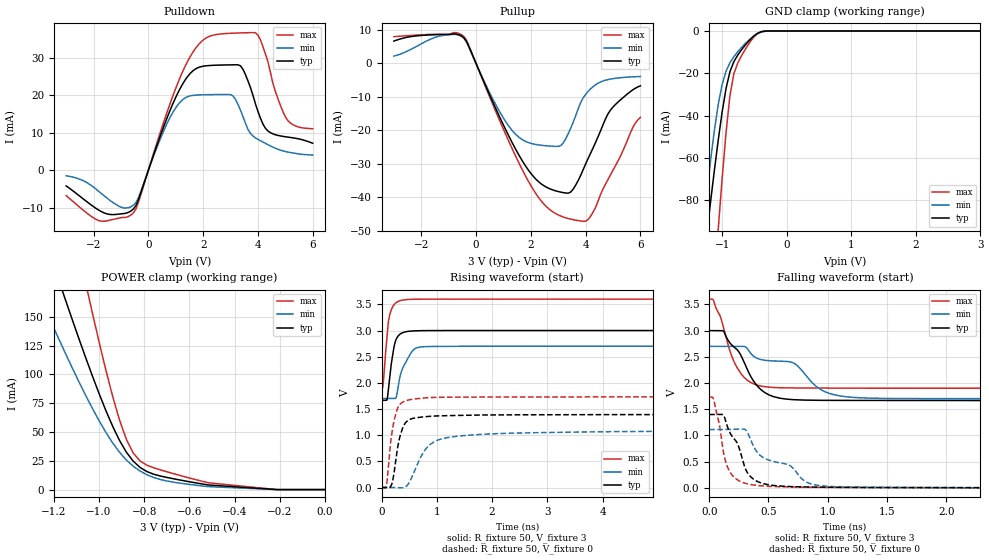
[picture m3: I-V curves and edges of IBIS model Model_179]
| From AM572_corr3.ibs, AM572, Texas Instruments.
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| Model based on original model for SDIO1833PB_H
|   Sub model 66OHMS_3
[model]   Model_179
|[Description]  [3V-I/O-X-X]
|   , ,
|[Input Load]
|[Output Drive]
|Voltage   3V
|Mode   I/O
Model_type   I/O
Polarity   Non-Inverting
Enable   Active-Low
Vinl =   0.75
Vinh =   1.875
Cref =   15.0000pF
Rref =   100.0000M
Vref =   0V
Vmeas =   1.5
C_comp   5p   5p   5p
[Model Spec]
Vinl   0.75   0.675   0.9
Vinh   1.875   1.6875   2.25
[Temperature Range]   25   125   -40
[Voltage Range]   3   2.7   3.6
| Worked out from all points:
|   slope of the pulldown table from 0 to 0.45 V, typ, clamps not added: 47.7 ohm
|   slope of the pullup table from 0 to 0.45 V, typ, clamps not added: 52.5 ohm
|   GND clamp passes 1 mA (typ) near -0.44 V on its own axis
|   rising waveform, R_fixture 50, V_fixture 3: 20-80 % time 105ps typ, 196ps min, 91ps max; typ from 1.67 V to 3 V
|   rising waveform, R_fixture 50, V_fixture 0: 20-80 % time 150ps typ, 422ps min, 132ps max; typ from 0 V to 1.4 V
|   falling waveform, R_fixture 50, V_fixture 3: 20-80 % time 223ps typ, 544ps min, 154ps max; typ from 3 V to 1.67 V
|   falling waveform, R_fixture 50, V_fixture 0: 20-80 % time 164ps typ, 406ps min, 97.3ps max; typ from 1.4 V to 0 V
[POWER_clamp]
-3V       1.325A     1.066A     2.083A
-1.273V   237.5mA    172.4mA    376.8mA
-1.242V   219.5mA    158.9mA    348.1mA
-1.152V   166.4mA    119.5mA    263mA
-1.061V   115.4mA    82.4mA     180.6mA
-1.03V    99.16mA    70.84mA    154.1mA
-969.7mV  68.62mA    49.67mA    103.8mA
-909.1mV  42.6mA     32.36mA    60.24mA
-878.8mV  32.4mA     25.65mA    43.46mA
-818.2mV  19.2mA     16.11mA    24.78mA
-515.2mV  4.001mA    2.562mA    5.883mA
0V        300.2nA    570.7nA    4.935uA
[Pulldown]
-3V       -4.151mA   -1.456mA   -6.73mA
-1.727V   -10.94mA   -6.093mA   -13.52mA
-545.5mV  -10.3mA    -9.288mA   -11.31mA
1V        19.41mA    16.64mA    21.82mA
1.636V    26.52mA    19.93mA    31.53mA
2.364V    27.93mA    20.14mA    35.94mA
3.091V    28.06mA    19.77mA    36.48mA
3.364V    27.79mA    15.98mA    36.55mA
4V        15.67mA    8.228mA    36mA
4.364V    10.47mA    6.836mA    28.93mA
5V        8.926mA    4.995mA    14.24mA
6V        7.203mA    4.061mA    11.06mA
[Pullup]
-3V       6.677mA    2.2mA      7.993mA
-1.364V   8.626mA    8.107mA    8.713mA
-454.5mV  7.757mA    7.619mA    8.133mA
727.3mV   -13.64mA   -12.44mA   -14.49mA
1.455V    -25.79mA   -21.27mA   -27.89mA
2.364V    -35.93mA   -24.47mA   -40.98mA
3V        -38.32mA   -24.81mA   -45.32mA
3.273V    -38.77mA   -22.56mA   -46.17mA
3.545V    -37.61mA   -17.6mA    -46.74mA
4.182V    -26.86mA   -7.609mA   -45.69mA
4.909V    -13.93mA   -4.678mA   -33.32mA
6V        -6.705mA   -3.917mA   -16.11mA
[GND_clamp]
-3V       -611.3mA   -669.6mA   -1.002A
-1.303V   -113.3mA   -94.63mA   -198.1mA
-1.242V   -97.2mA    -77.77mA   -171.3mA
-1.182V   -81.45mA   -61.83mA   -144.9mA
-1.061V   -51.68mA   -34.78mA   -93.82mA
-1V       -38.37mA   -25.24mA   -69.83mA
-939.4mV  -27.14mA   -18.97mA   -48.01mA
-878.8mV  -19.2mA    -15.02mA   -30.51mA
-818.2mV  -14.5mA    -12.17mA   -20.19mA
-697mV    -8.773mA   -7.671mA   -11.56mA
-454.5mV  -1.145mA   -1.361mA   -1.238mA
3V        300.2nA    77.91uA    4.624uA
[Ramp]
dV/dt_f 0.80097728/0.22325901n 0.59949493/0.54393269n  1.0201677/0.15414011n
dV/dt_r 0.84283897/0.15019004n  0.6706711/0.42152466n  1.0433816/0.13162427n
R_load =  50
[Rising Waveform]
R_fixture =  50
V_fixture =  3
V_fixture_min =  2.7
V_fixture_max =  3.6
0s        1.665V     1.701V     1.9V
28.9ps    1.665V     1.701V     1.966V
98.3ps    1.674V     1.701V     2.888V
117.9ps   1.81V      1.701V     3.12V
146.9ps   2.102V     1.701V     3.294V
250.1ps   2.791V     1.702V     3.52V
390.2ps   2.962V     2.295V     3.584V
574.5ps   2.993V     2.628V     3.597V
807.2ps   2.999V     2.692V     3.599V
10.02ns   3V         2.7V       3.6V
[Rising Waveform]
R_fixture =  50
V_fixture =  0
V_fixture_min =  0
V_fixture_max =  0
0s        0V         0V         0V
90.4ps    0V         0V         50.69mV
191ps     83.11mV    0V         1.066V
270.7ps   617.8mV    -2.568mV   1.456V
387.5ps   1.148V     -4.261mV   1.635V
556.2ps   1.318V     215.9mV    1.687V
741.6ps   1.348V     646mV      1.707V
882.5ps   1.361V     824mV      1.719V
1.44ns    1.38V      987.5mV    1.727V
10.01ns   1.398V     1.111V     1.733V
[Falling Waveform]
R_fixture =  50
V_fixture =  3
V_fixture_min =  2.7
V_fixture_max =  3.6
0s        3V         2.7V       3.6V
35.8ps    2.999V     2.7V       3.578V
118.9ps   2.993V     2.7V       3.073V
252.5ps   2.587V     2.7V       2.23V
386.4ps   1.998V     2.491V     1.974V
515.7ps   1.763V     2.424V     1.918V
710.5ps   1.682V     2.383V     1.906V
1.008ns   1.669V     1.807V     1.902V
1.353ns   1.667V     1.711V     1.9V
10.02ns   1.665V     1.701V     1.9V
[Falling Waveform]
R_fixture =  50
V_fixture =  0
V_fixture_min =  0
V_fixture_max =  0
0s        1.399V     1.112V     1.732V
39.1ps    1.399V     1.112V     1.676V
120.6ps   1.389V     1.113V     676.1mV
172.5ps   1.062V     1.116V     310.3mV
308.3ps   348.7mV    1.104V     84.02mV
441.4ps   91.02mV    598.6mV    37.9mV
681.2ps   24.77mV    425.4mV    16.51mV
837.7ps   16.09mV    92.3mV     10.63mV
1.1ns     9.13mV     19.24mV    8.48mV
10.01ns   0V         0V         0V
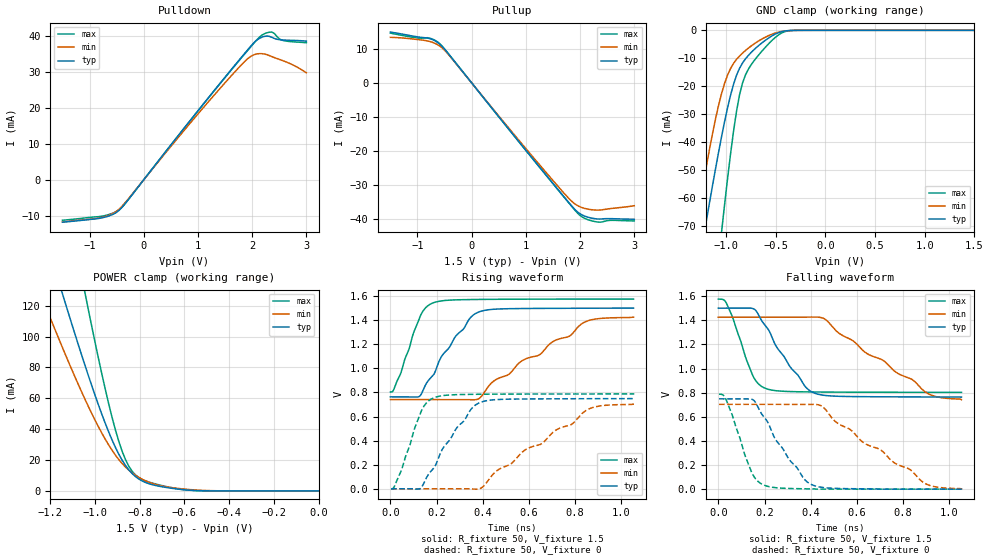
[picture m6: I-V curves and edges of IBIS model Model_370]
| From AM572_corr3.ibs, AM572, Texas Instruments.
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| Model based on original model for DDR_SEIOPB_V
|   Sub model SR110_DRV48_1P5
[model]   Model_370
|[Description]  [1.5V-I/O-X-X]
|   , ,
|[Input Load]
|[Output Drive]
|Voltage   1.5V
|Mode   I/O
Model_type   I/O
Polarity   Non-Inverting
Enable   Active-Low
Vinl =   0.65
Vinh =   0.85
Cref =   15.0000pF
Rref =   100.0000M
Vref =   0V
Vmeas =   0.75
C_comp   2p   2p   2p
[Model Spec]
Vinl   0.65   0.6125   0.6875
Vinh   0.85   0.8125   0.8875
[Receiver Thresholds]
Tslew_ac =  0.5n
Vth =  0.75
Vth_max =  0.7875
Vth_min =  0.675
Vinh_ac =  0.175
Vinh_dc =  0.1
Vinl_ac =  -0.175
Vinl_dc =  -0.1
[Temperature Range]   25   125   -40
[Voltage Range]   1.5   1.425   1.575
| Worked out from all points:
|   slope of the pulldown table from 0 to 0.225 V, typ, clamps not added: 51.5 ohm
|   slope of the pullup table from 0 to 0.225 V, typ, clamps not added: 50.1 ohm
|   GND clamp passes 1 mA (typ) near -0.48 V on its own axis
|   POWER clamp passes 1 mA (typ) near -0.62 V on its own axis
|   rising waveform, R_fixture 50, V_fixture 1.5: 20-80 % time 155ps typ, 351ps min, 82ps max; typ from 0.763 V to 1.5 V
|   rising waveform, R_fixture 50, V_fixture 0: 20-80 % time 152ps typ, 346ps min, 81.9ps max; typ from 0 V to 0.749 V
|   falling waveform, R_fixture 50, V_fixture 1.5: 20-80 % time 151ps typ, 332ps min, 83ps max; typ from 1.5 V to 0.763 V
|   falling waveform, R_fixture 50, V_fixture 0: 20-80 % time 153ps typ, 338ps min, 82.7ps max; typ from 0.749 V to 0 V
[POWER_clamp]
-1.5V     302.8mA    223.9mA    484.4mA
-1.242V   174.3mA    127.3mA    279.1mA
-1.136V   123.3mA    89.68mA    196.8mA
-1.045V   81.65mA    59.62mA    128.8mA
-1.03V    75mA       54.92mA    117.8mA
-939.4mV  38.44mA    29.91mA    56.84mA
-893.9mV  23.93mA    20.41mA    32.31mA
-848.5mV  13.61mA    13.43mA    15.91mA
-803mV    7.623mA    8.663mA    8.564mA
-712.1mV  3.022mA    3.561mA    3.877mA
-575.8mV  470.5uA    872uA      449uA
0V        112.6nA    435.6nA    613.8nA
[Pulldown]
-1.5V     -11.81mA   -11.79mA   -11.27mA
-727.3mV  -10.45mA   -10.3mA    -10mA
-545.5mV  -9.463mA   -9.189mA   -9.136mA
-409.1mV  -7.817mA   -7.49mA    -7.751mA
1.227V    23.47mA    22.31mA    23.4mA
1.818V    34.37mA    32.24mA    34.22mA
2V        37.61mA    34.55mA    37.45mA
2.136V    39.37mA    35.1mA     39.71mA
2.318V    39.9mA     34.55mA    41.07mA
2.409V    39.32mA    34mA       40.72mA
2.545V    38.91mA    33.26mA    38.88mA
3V        38.57mA    29.76mA    38.14mA
[Pullup]
-1.5V     14.98mA    13.43mA    14.66mA
-1V       13.57mA    12.78mA    13.25mA
-772.7mV  13.05mA    12.2mA     13.19mA
-590.9mV  11.46mA    10.89mA    11.59mA
-409.1mV  8.169mA    8.001mA    8.195mA
1.409V    -27.86mA   -27.07mA   -27.94mA
1.773V    -34.91mA   -33.72mA   -35mA
1.909V    -37.4mA    -35.72mA   -37.61mA
2.045V    -38.99mA   -36.82mA   -39.6mA
2.273V    -40.02mA   -37.48mA   -40.87mA
2.591V    -40.02mA   -37mA      -40.5mA
3V        -40.19mA   -36.21mA   -40.69mA
[GND_clamp]
-1.5V     -133.6mA   -115.7mA   -234.3mA
-1.288V   -87.29mA   -67.59mA   -156.8mA
-1.197V   -68.11mA   -48.64mA   -124.4mA
-1.045V   -38.25mA   -22.77mA   -72.51mA
-1.015V   -32.88mA   -19.1mA    -62.74mA
-954.5mV  -23.3mA    -13.72mA   -44.4mA
-863.6mV  -13.6mA    -9.192mA   -23.11mA
-803mV    -10.18mA   -7.193mA   -15.89mA
-681.8mV  -5.771mA   -4.027mA   -9.287mA
-500mV    -1.264mA   -914.7uA   -2.429mA
-348.5mV  -52.39uA   -75.11uA   -85.87uA
1.5V      112.6nA    528.1nA    514.5nA
[Ramp]
dV/dt_f 0.44261194/0.15148339n 0.41148713/0.33291086n 0.46384002/83.101865p
dV/dt_r 0.45080353/0.153332n  0.42386076/0.34681697n 0.47355174/82.124572p
R_load =  50
[Rising Waveform]
R_fixture =  50
V_fixture =  1.5
V_fixture_min =  1.425
V_fixture_max =  1.575
0s        763.3mV    740.8mV    803.4mV
43.67ps   762.7mV    740.7mV    952.6mV
124.2ps   765.5mV    740.7mV    1.408V
184.1ps   939.3mV    740.8mV    1.543V
280.8ps   1.262V     740.5mV    1.568V
387.8ps   1.471V     754.5mV    1.572V
448.8ps   1.491V     896.3mV    1.573V
777.5ps   1.499V     1.27V      1.575V
836.8ps   1.499V     1.38V      1.575V
1.053ns   1.5V       1.425V     1.575V
[Rising Waveform]
R_fixture =  50
V_fixture =  0
V_fixture_min =  0
V_fixture_max =  0
3.146ps   0V         0V         0V
46.42ps   0V         0V         145.1mV
128.7ps   0V         0V         620mV
189.9ps   176.5mV    0V         756.9mV
286.1ps   502.5mV    0V         781.5mV
394.5ps   720.5mV    8.029mV    784.9mV
461.1ps   740.6mV    150.3mV    785.8mV
786.1ps   747.5mV    536.9mV    787.1mV
851.4ps   747.8mV    655mV      787.2mV
1.056ns   748.7mV    703.3mV    787.3mV
[Falling Waveform]
R_fixture =  50
V_fixture =  1.5
V_fixture_min =  1.425
V_fixture_max =  1.575
0s        1.5V       1.425V     1.575V
38.32ps   1.5V       1.425V     1.528V
151.5ps   1.496V     1.425V     932.7mV
206.4ps   1.349V     1.425V     833.7mV
311.5ps   1.012V     1.425V     808.9mV
419.9ps   793.8mV    1.427V     805.4mV
462.5ps   776.6mV    1.408V     804.7mV
637.5ps   766.4mV    1.132V     803.2mV
905.4ps   764.3mV    794.5mV    802.6mV
1.053ns   763.3mV    740.8mV    802.5mV
[Falling Waveform]
R_fixture =  50
V_fixture =  0
V_fixture_min =  0
V_fixture_max =  0
3.146ps   748.7mV    703.3mV    787.3mV
35.11ps   748.8mV    703.3mV    735.2mV
146.9ps   744mV      703.3mV    129.9mV
199.1ps   594.8mV    703.3mV    32.5mV
306.4ps   247mV      703.2mV    5.751mV
413.2ps   30.46mV    703.2mV    2.108mV
450.1ps   14.48mV    685.6mV    0V
512.2ps   6.193mV    552.3mV    0V
892.7ps   0V         49.98mV    0V
1.056ns   0V         0V         0V
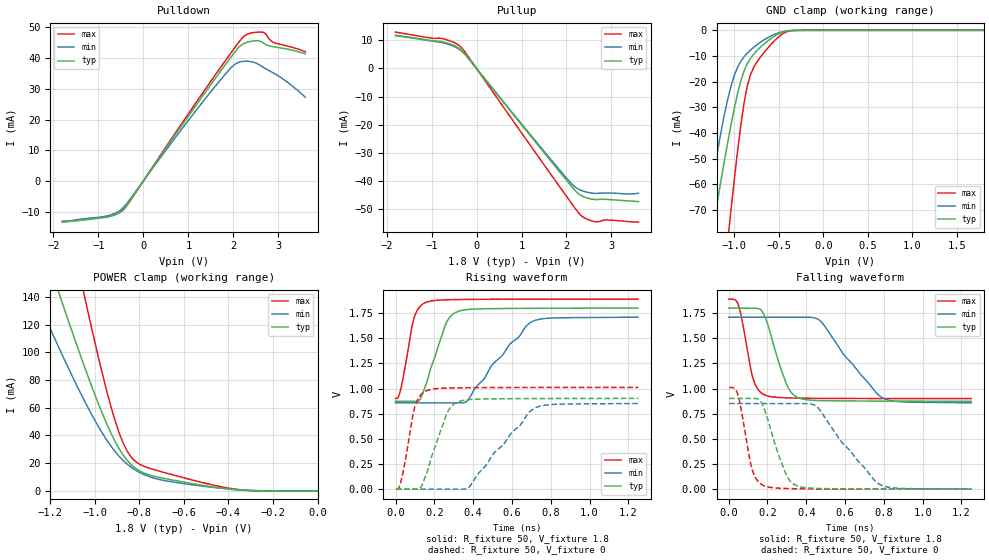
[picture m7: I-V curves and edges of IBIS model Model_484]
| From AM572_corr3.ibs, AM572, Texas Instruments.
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| Model based on original model for DDR_DIFFIOPB_H
|   Sub model SR001_DRV48_1P8
[model]   Model_484
|[Description]  [1.8V-I/O-X-X]
|   , ,
|[Input Load]
|[Output Drive]
|Voltage   1.8V
|Mode   I/O
Model_type   I/O
Polarity   Non-Inverting
Enable   Active-Low
Vinl =   0.775
Vinh =   1.025
Cref =   15.0000pF
Rref =   100.0000M
Vref =   0V
Vmeas =   0.9
C_comp   2p   2p   2p
[Model Spec]
Vinl   0.78   0.735   0.825
Vinh   1.02   0.975   1.065
[Receiver Thresholds]
Tslew_ac =  0.5n
Vth =  0.9
Vth_max =  0.945
Vth_min =  0.81
Vinh_ac =  0.2
Vinh_dc =  0.125
Vinl_ac =  -0.2
Vinl_dc =  -0.125
[Temperature Range]   25   125   -40
[Voltage Range]   1.8   1.71   1.89
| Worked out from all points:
|   slope of the pulldown table from 0 to 0.27 V, typ, clamps not added: 46.9 ohm
|   slope of the pullup table from 0 to 0.27 V, typ, clamps not added: 49.7 ohm
|   GND clamp passes 1 mA (typ) near -0.48 V on its own axis
|   POWER clamp passes 1 mA (typ) near -0.38 V on its own axis
|   rising waveform, R_fixture 50, V_fixture 1.8: 20-80 % time 93ps typ, 224ps min, 55.8ps max; typ from 0.874 V to 1.8 V
|   rising waveform, R_fixture 50, V_fixture 0: 20-80 % time 93.7ps typ, 225ps min, 55.9ps max; typ from 0 V to 0.903 V
|   falling waveform, R_fixture 50, V_fixture 1.8: 20-80 % time 89.9ps typ, 208ps min, 58.2ps max; typ from 1.8 V to 0.874 V
|   falling waveform, R_fixture 50, V_fixture 0: 20-80 % time 91.4ps typ, 211ps min, 57.4ps max; typ from 0.903 V to 0 V
[POWER_clamp]
-1.8V     464.6mA    344.4mA    740.8mA
-1.273V   197mA      143.3mA    314.4mA
-1.164V   144mA      104.2mA    229mA
-1.145V   135.3mA    97.86mA    215mA
-1.055V   93.25mA    67.59mA    146.5mA
-1.036V   85.18mA    61.89mA    133.3mA
-909.1mV  35.72mA    28.41mA    50.73mA
-872.7mV  25.87mA    21.94mA    34.5mA
-818.2mV  16.45mA    15.08mA    21.33mA
-690.9mV  9.084mA    7.592mA    13.42mA
-400mV    1.38mA     1.43mA     2.039mA
0V        227.3nA    761nA      1.176uA
[Pulldown]
-1.8V     -13.45mA   -13.11mA   -13.3mA
-818.2mV  -11.81mA   -11.44mA   -11.72mA
-600mV    -10.83mA   -10.36mA   -10.81mA
-436.4mV  -9.068mA   -8.512mA   -9.288mA
1.255V    26.38mA    24.53mA    27.32mA
1.855V    38.53mA    35.35mA    39.84mA
2.073V    42.76mA    38.34mA    44.25mA
2.291V    45.11mA    39mA       47.65mA
2.618V    45.4mA     37.45mA    48.49mA
2.727V    44.4mA     36.48mA    47.76mA
2.891V    43.71mA    35.16mA    45.15mA
3.6V      41.36mA    27.26mA    42.08mA
[Pullup]
-1.8V     11.9mA     11.66mA    12.97mA
-1.036V   10.04mA    9.888mA    10.91mA
-763.6mV  9.523mA    9.186mA    10.68mA
-490.9mV  8.144mA    7.787mA    9.204mA
-327.3mV  6.377mA    6.133mA    7.311mA
2.018V    -40.23mA   -39.43mA   -46mA
2.182V    -43.37mA   -42.12mA   -49.65mA
2.345V    -45.48mA   -43.6mA    -52.72mA
2.509V    -46.4mA    -44.3mA    -54.07mA
2.673V    -46.74mA   -44.55mA   -54.7mA
2.891V    -46.69mA   -44.38mA   -54.01mA
3.6V      -47.48mA   -44.49mA   -54.81mA
[GND_clamp]
-1.8V     -200.8mA   -187.9mA   -345.9mA
-1.327V   -95.75mA   -76.22mA   -171.1mA
-1.255V   -80.19mA   -60.47mA   -144.9mA
-1.218V   -72.53mA   -52.92mA   -131.9mA
-1.073V   -43.32mA   -26.59mA   -81.54mA
-1.036V   -36.61mA   -21.6mA    -69.55mA
-963.6mV  -24.61mA   -14.37mA   -47.01mA
-854.5mV  -12.98mA   -8.864mA   -21.66mA
-781.8mV  -9.263mA   -6.573mA   -14.36mA
-672.7mV  -5.498mA   -3.827mA   -8.897mA
-345.5mV  -48.81uA   -73.08uA   -79.37uA
1.8V      227.3nA    3.986uA    988nA
[Ramp]
dV/dt_f 0.55606231/89.915686p 0.51144232/0.20829208n 0.59372174/58.226748p
dV/dt_r 0.54258756/93.824964p 0.51195479/0.22563911n 0.60775716/55.94697p
R_load =  50
[Rising Waveform]
R_fixture =  50
V_fixture =  1.8
V_fixture_min =  1.71
V_fixture_max =  1.89
0s        873.8mV    858.6mV    901.6mV
28.74ps   873.2mV    858.6mV    1.01V
95.32ps   872.8mV    858.6mV    1.701V
125.4ps   889.4mV    858.6mV    1.815V
155.7ps   1.033V     858.6mV    1.857V
259.6ps   1.645V     858.4mV    1.883V
321.7ps   1.767V     857.4mV    1.885V
371.7ps   1.786V     881.2mV    1.887V
704.3ps   1.798V     1.666V     1.89V
1.25ns    1.8V       1.71V      1.89V
[Rising Waveform]
R_fixture =  50
V_fixture =  0
V_fixture_min =  0
V_fixture_max =  0
2.24ps    0V         0V         0V
33.02ps   0V         0V         115mV
100.2ps   0V         0V         823.4mV
130ps     17.05mV    0V         938.1mV
160.7ps   159.6mV    0V         979.9mV
264.4ps   751.7mV    0V         1.005V
325.7ps   870.6mV    0V         1.007V
380.6ps   890.9mV    23.63mV    1.009V
720.9ps   901mV      808.4mV    1.011V
1.252ns   902.5mV    851.6mV    1.011V
[Falling Waveform]
R_fixture =  50
V_fixture =  1.8
V_fixture_min =  1.71
V_fixture_max =  1.89
0s        1.8V       1.71V      1.89V
48.84ps   1.8V       1.71V      1.837V
124.9ps   1.8V       1.71V      1.105V
188.3ps   1.706V     1.71V      934.8mV
298.4ps   1.044V     1.71V      908mV
358ps     909.6mV    1.71V      905.5mV
473.8ps   880.9mV    1.671V     903mV
595.4ps   877.6mV    1.333V     901.8mV
797.2ps   875.4mV    903.9mV    901mV
1.25ns    873.8mV    858.6mV    900.8mV
[Falling Waveform]
R_fixture =  50
V_fixture =  0
V_fixture_min =  0
V_fixture_max =  0
2.24ps    902.5mV    851.6mV    1.011V
44.42ps   902.7mV    851.6mV    956.5mV
119.7ps   902.5mV    851.6mV    204.9mV
181.6ps   807.6mV    851.6mV    34.8mV
292.5ps   162.1mV    851.6mV    6.803mV
352.6ps   33.22mV    851.4mV    4.01mV
456.9ps   7.091mV    816mV      0V
578.1ps   3.417mV    478.9mV    0V
783.6ps   0V         42.23mV    0V
1.252ns   0V         0V         0V
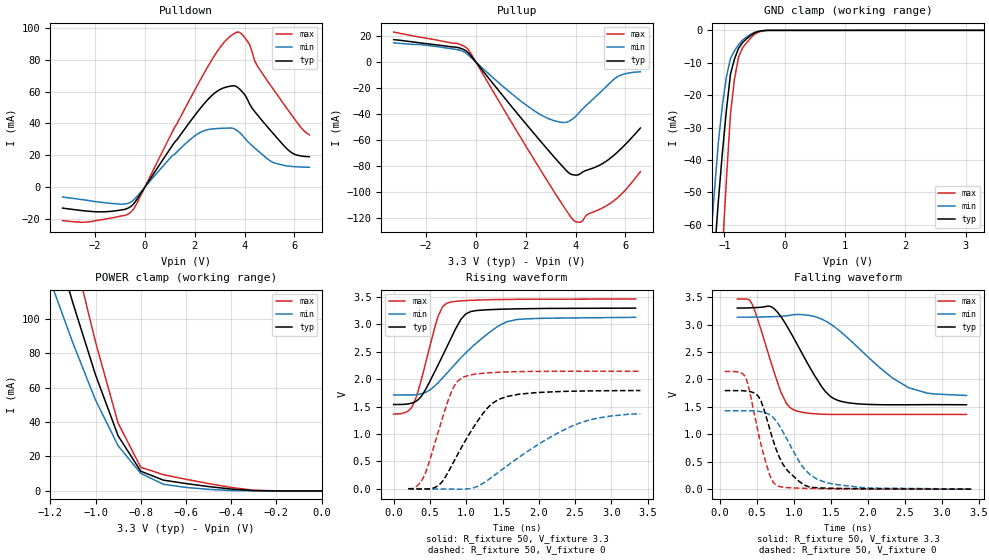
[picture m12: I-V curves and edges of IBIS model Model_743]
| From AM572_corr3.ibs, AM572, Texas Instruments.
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| Model based on original model for BC1833DV40DCPBFBP1811_SSCEV
|   Sub model BC40D_V_5P_SC1_3P3
[model]   Model_743
|[Description]  [3.3V-I/O-X-40C CLASS MODE SLOW MODE, IND, 5 PERCENT%]
|   40C CLASS MODE SLOW MODE, ,IND,5 PERCENT%
|[Input Load]
|[Output Drive] 40C CLASS MODE SLOW MODE
|Voltage   3.3V
|Mode   I/O
Model_type   I/O
Polarity   Non-Inverting
Enable   Active-Low
Vinl =   0.8V
Vinh =   2V
Cref =   15pF
Rref =   100.0000M
Vref =   0V
Vmeas =   1.65
C_comp   2.155p   1.84p   2.47p
[Model Spec]
Vinl   0.8V   0.8V   0.8V
Vinh   2V   2V   2V
D_overshoot_ampl_h 0.66 0.66 0.66
D_overshoot_ampl_l 0.66 0.66 0.66
D_overshoot_area_h 0.33n 0.33n 0.33n
D_overshoot_area_l 0.33n 0.33n 0.33n
D_overshoot_high 3.96 3.96 3.96
D_overshoot_low -0.66 -0.66 -0.66
D_overshoot_time 1n 1n 1n
S_overshoot_high 3.3 3.3 3.3
S_overshoot_low 0 0 0
[Temperature Range]   25   125   -40
[Voltage Range]   3.3   3.135   3.465
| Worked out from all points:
|   slope of the pulldown table from 0 to 0.495 V, typ, clamps not added: 41.8 ohm
|   slope of the pullup table from 0 to 0.495 V, typ, clamps not added: 41.4 ohm
|   GND clamp passes 1 mA (typ) near -0.52 V on its own axis
|   POWER clamp passes 1 mA (typ) near -0.39 V on its own axis
|   rising waveform, R_fixture 50, V_fixture 3.3: 20-80 % time 394ps typ, 656ps min, 251ps max; typ from 1.54 V to 3.3 V
|   rising waveform, R_fixture 50, V_fixture 0: 20-80 % time 494ps typ, 956ps min, 305ps max; typ from 0 V to 1.79 V
|   falling waveform, R_fixture 50, V_fixture 3.3: 20-80 % time 448ps typ, 726ps min, 298ps max; typ from 3.3 V to 1.54 V
|   falling waveform, R_fixture 50, V_fixture 0: 20-80 % time 302ps typ, 392ps min, 221ps max; typ from 1.8 V to 0.001 V
[POWER_clamp]
-3.3V     1.165A     1.199A     1.459A
-1.2V     153.4mA    122mA      196.7mA
-1.167V   138.6mA    109.9mA    177.9mA
-1.1V     109.1mA    85.82mA    140.3mA
-1.067V   95.17mA    74.81mA    122.3mA
-1.033V   81.28mA    63.8mA     104.4mA
-900mV    31.99mA    26.2mA     39.32mA
-800mV    11.44mA    10.23mA    13.72mA
-700mV    6.266mA    3.859mA    9.425mA
-600mV    4.272mA    2.025mA    6.774mA
-300mV    202.9uA    25.89uA    394.5uA
0V        3.057uA    1.331uA    6.945uA
[Pulldown]
-3.3V     -13.12mA   -6.17mA    -20.99mA
-1.6V     -15.42mA   -9.77mA    -20.03mA
-500mV    -11.32mA   -8.73mA    -14.74mA
1.1V      26.03mA    19.72mA    34.55mA
2.1V      46.97mA    33.23mA    63.68mA
2.9V      60.17mA    36.78mA    85.02mA
3.7V      62.88mA    35.56mA    97.27mA
4.2V      52.25mA    27.53mA    89.51mA
4.5V      45.65mA    23.34mA    76.43mA
5V        36.36mA    16.8mA     64.86mA
5.7V      24.04mA    13.33mA    49.37mA
6.6V      19.1mA     12.5mA     32.8mA
[Pullup]
-3.3V     17.3mA     14.8mA     23.1mA
-800mV    11.5mA     9.816mA    14.62mA
-300mV    7.112mA    5.353mA    9.539mA
1.4V      -33.47mA   -23.81mA   -45.48mA
2.6V      -61.08mA   -40.53mA   -83.28mA
3.5V      -80.87mA   -46.53mA   -110.6mA
3.8V      -86.3mA    -44.88mA   -119.1mA
4V        -87.06mA   -41.92mA   -123mA
4.2V      -85.82mA   -37.73mA   -123.3mA
4.5V      -82.97mA   -32.09mA   -117.1mA
5.6V      -70.75mA   -12.32mA   -105.9mA
6.6V      -50.83mA   -7.45mA    -84.37mA
[GND_clamp]
-3.3V     -675.1mA   -831.9mA   -985.9mA
-1.233V   -86.22mA   -66.38mA   -141.8mA
-1.167V   -69.2mA    -49.86mA   -116.5mA
-1.1V     -52.6mA    -34.38mA   -91.44mA
-1.033V   -37.65mA   -22.95mA   -67.83mA
-966.7mV  -24.63mA   -14.38mA   -45.95mA
-900mV    -13.56mA   -8.682mA   -25.81mA
-833.3mV  -8.843mA   -6.325mA   -15.09mA
-766.7mV  -5.582mA   -4.435mA   -8.297mA
-700mV    -3.779mA   -3.012mA   -5.442mA
-500mV    -752.8uA   -575.1uA   -1.188mA
3.3V      3.057uA    1.928uA    6.853uA
[Ramp]
dV/dt_f   1.07874/0.45784833n   0.88698/0.74972001n   1.26582/0.29870064n
dV/dt_r  1.0823224/0.49655787n 0.86293032/1.0322981n  1.2922384/0.30607791n
R_load =  50
[Rising Waveform]
R_fixture =  50
V_fixture =  3.3
V_fixture_min =  3.135
V_fixture_max =  3.465
0s        1.537V     1.712V     1.362V
181.9ps   1.546V     1.712V     1.407V
273.5ps   1.574V     1.712V     1.548V
408.3ps   1.74V      1.745V     2.13V
618ps     2.275V     1.943V     3.17V
740.8ps   2.613V     2.121V     3.391V
927ps     3.093V     2.391V     3.43V
993.4ps   3.192V     2.48V      3.436V
1.557ns   3.281V     3.049V     3.457V
3.333ns   3.298V     3.13V      3.464V
[Rising Waveform]
R_fixture =  50
V_fixture =  0
V_fixture_min =  0
V_fixture_max =  0
200.7ps   -476.5uV   -119.3uV   967.4uV
299.2ps   -5.174mV   -119.3uV   26.97mV
399.9ps   -6.448mV   -303.3uV   178.1mV
638.2ps   83.95mV    -5.449mV   1.143V
812.2ps   453.4mV    -7.296mV   1.816V
962.1ps   818.4mV    -7.506mV   2.039V
1.299ns   1.482V     158mV      2.116V
1.563ns   1.685V     418mV      2.133V
2.537ns   1.782V     1.186V     2.146V
3.399ns   1.793V     1.365V     2.147V
[Falling Waveform]
R_fixture =  50
V_fixture =  3.3
V_fixture_min =  3.135
V_fixture_max =  3.465
236.9ps   3.3V       3.135V     3.464V
438.7ps   3.306V     3.136V     3.366V
734.8ps   3.288V     3.145V     2.129V
898.7ps   2.989V     3.159V     1.564V
998.9ps   2.753V     3.18V      1.446V
1.373ns   1.875V     3.101V     1.366V
1.589ns   1.622V     2.916V     1.362V
2.176ns   1.539V     2.197V     1.363V
2.551ns   1.538V     1.849V     1.362V
3.333ns   1.539V     1.707V     1.362V
[Falling Waveform]
R_fixture =  50
V_fixture =  0
V_fixture_min =  0
V_fixture_max =  0
65.94ps   1.797V     1.429V     2.146V
350.3ps   1.789V     1.429V     2.029V
533.5ps   1.665V     1.418V     944.9mV
685.8ps   1.042V     1.346V     218.9mV
771.6ps   690.9mV    1.223V     64.62mV
887.7ps   384.4mV    959.6mV    30.88mV
1.074ns   139.6mV    501.7mV    18.74mV
1.218ns   40.72mV    266.8mV    14.45mV
1.411ns   19.99mV    131.5mV    8.086mV
3.399ns   816.6uV    2.901mV    597.4uV
